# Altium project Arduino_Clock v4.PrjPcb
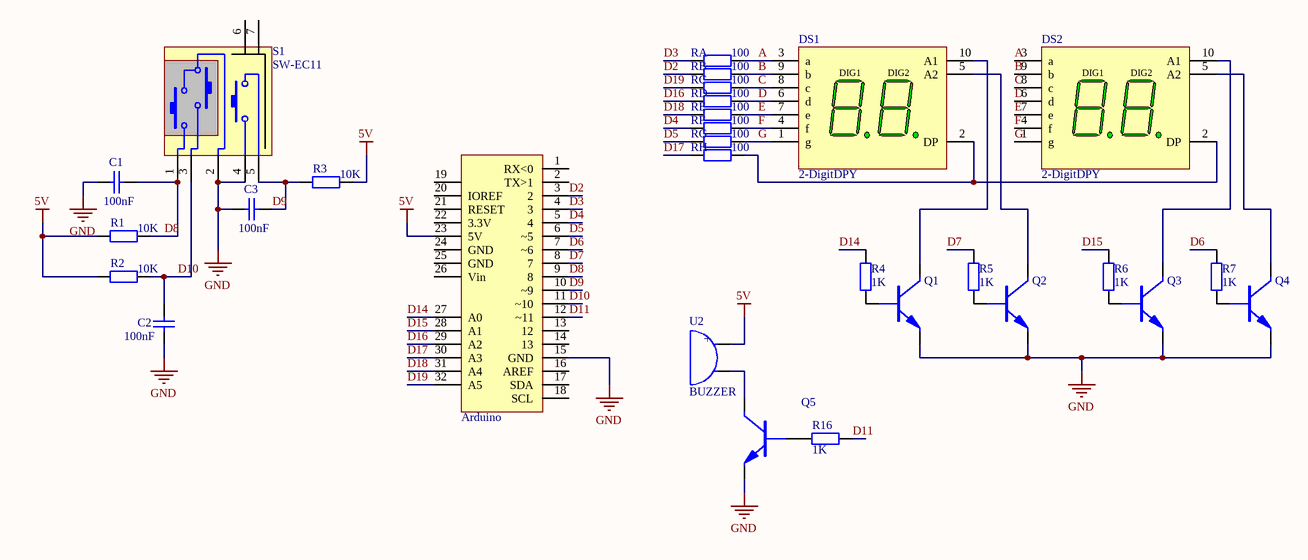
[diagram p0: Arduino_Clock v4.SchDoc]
1 sheet, 29 parts. Net scope: global (net labels, ports and power ports of the same name join across sheets).
Board file: Arduino_Clock v4.PcbDoc

## Sheet Arduino_Clock v4.SchDoc
size A4

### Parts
C1  value 100nF  [RAD0.2]  (hidden comment: Cap)
C2  value 100nF  [RAD0.2]  (hidden comment: Cap)
C3  value 100nF  [RAD0.2]  (hidden comment: Cap)
DS1  2-DigitDPY  [2-DigitDPY]
DS2  2-DigitDPY  [2-DigitDPY]
Q1  NPN  [NPN]  (value not drawn)
Q2  NPN  [NPN]  (value not drawn)
Q3  NPN  [NPN]  (value not drawn)
Q4  NPN  [NPN]  (value not drawn)
Q5  NPN  [NPN]  (value not drawn)
R1  value 10K  [AXIAL-0.4]  (hidden comment: Res2)
R2  value 10K  [AXIAL-0.4]  (hidden comment: Res2)
R3  value 10K  [AXIAL-0.4]  (hidden comment: Res2)
R4  value 1K  [AXIAL-0.4]  (hidden comment: Res2)
R5  value 1K  [AXIAL-0.4]  (hidden comment: Res2)
R6  value 1K  [AXIAL-0.4]  (hidden comment: Res2)
R7  value 1K  [AXIAL-0.4]  (hidden comment: Res2)
R16  value 1K  [AXIAL-0.4]  (hidden comment: Res2)
RA  value 100  [AXIAL-0.4]  (hidden comment: Res2)
RB  value 100  [AXIAL-0.4]  (hidden comment: Res2)
RC  value 100  [AXIAL-0.4]  (hidden comment: Res2)
RD  value 100  [AXIAL-0.4]  (hidden comment: Res2)
RE  value 100  [AXIAL-0.4]  (hidden comment: Res2)
RF  value 100  [AXIAL-0.4]  (hidden comment: Res2)
RG  value 100  [AXIAL-0.4]  (hidden comment: Res2)
RH  value 100  [AXIAL-0.4]  (hidden comment: Res2)
S1  SW-EC11  [EC11]
U1  Arduino  [Arduino-UNO]
U2  BUZZER  [Buzzer]

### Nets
5V: R1.1 R2.1 R3.2 U1.23(5V) U2.1(A)
GND: C1.1 C2.1 C3.1 Q1.1(E) Q2.1(E) Q3.1(E) Q4.1(E) Q5.1(E) S1.2 S1.4 U1.15(GND)
A: DS1.3(a) DS2.3(a) RA.2
B: DS1.9(b) DS2.9(b) RB.2
C: DS1.8(c) DS2.8(c) RC.2
D: DS1.6(d) DS2.6(d) RD.2
D2: RB.1 U1.3(2)
D3: RA.1 U1.4(3)
D4: RF.1 U1.5(4)
D5: RG.1 U1.6(~5)
D6: R7.2 U1.7(~6)
D7: R5.1 U1.8(7)
D8: C1.2 R1.2 S1.1 U1.9(8)
D9: C3.2 R3.1 S1.5 U1.10(~9)
D10: C2.2 R2.2 S1.3 U1.11(~10)
D11: R16.1 U1.12(~11)
D14: R4.2 U1.27(A0)
D15: R6.2 U1.28(A1)
D16: RD.1 U1.29(A2)
D17: RH.1 U1.30(A3)
D18: RE.1 U1.31(A4)
D19: RC.1 U1.32(A5)
E: DS1.7(e) DS2.7(e) RE.2
F: DS1.4(f) DS2.4(f) RF.2
G: DS1.1(g) DS2.1(g) RG.2
NetDS1_2: DS1.2(DP) DS2.2(DP) RH.2
NetDS1_5: DS1.5(A2) Q2.3(C)
NetDS1_10: DS1.10(A1) Q1.3(C)
NetDS2_5: DS2.5(A2) Q4.3(C)
NetDS2_10: DS2.10(A1) Q3.3(C)
NetQ1_2: Q1.2(B) R4.1
NetQ2_2: Q2.2(B) R5.2
NetQ3_2: Q3.2(B) R6.1
NetQ4_2: Q4.2(B) R7.1
NetQ5_2: Q5.2(B) R16.2
NetQ5_3: Q5.3(C) U2.2(B)

Not connected (* = marked no-connect by the designer): S1 6 7; U1 1(RX<0) 2(TX>1) 13(12) 14(13) 16(AREF) 17(SDA) 18(SCL) 19 20(IOREF) 21(RESET) 22(3.3V) 24(GND) 25(GND) 26(Vin)

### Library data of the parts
C1-C3 = Cap: Capacitor
DS1 DS2 = 2-DigitDPY: 9.2 mm Green 7-Segment Display: 2-Digit, RH DP; LuminousIntensity: 1100 ucd (Minimum).
Q1-Q5 = NPNLXH: NPN Transistor
R1-R7 R16 RA RB RC RD RE RF RG RH = Res2: Resistor
S1 = SW-EC11: 旋转编码开关
U1 = Arduino-UNO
